VERSION 5.8 ;
BUSBITCHARS "[]" ;
DIVIDERCHAR "/" ;
UNITS
    DATABASE MICRONS 1000 ;
END UNITS

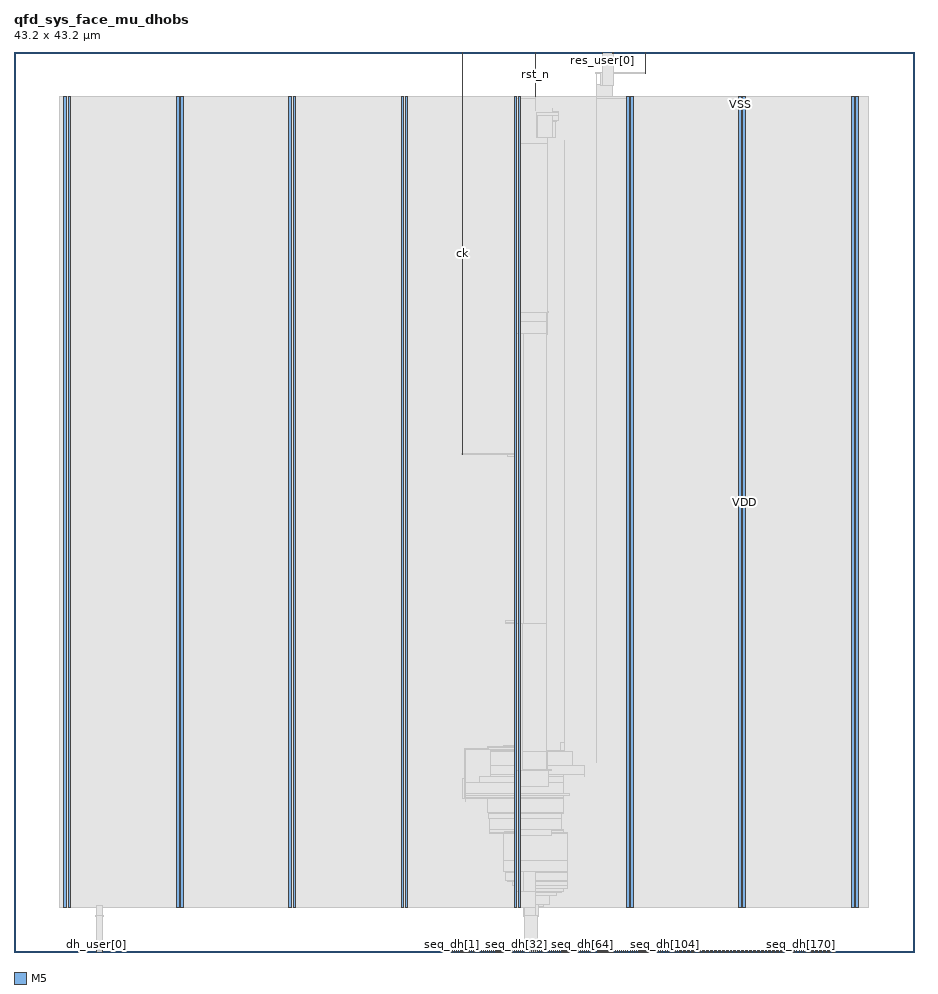
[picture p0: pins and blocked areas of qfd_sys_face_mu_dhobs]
MACRO qfd_sys_face_mu_dhobs
  FOREIGN qfd_sys_face_mu_dhobs 0 0 ;
  CLASS BLOCK ;
  SIZE 43.2 BY 43.2 ;
  PIN ck
    DIRECTION INPUT ;
    USE SIGNAL ;
    PORT
      LAYER M5 ;
        RECT  21.504 43.116 21.528 43.2 ;
    END
    PORT
      LAYER M5 ;
        RECT  21.504 23.893 21.528 43.152 ;
    END
  END ck
  PIN dh_user[0]
    DIRECTION OUTPUT ;
    USE SIGNAL ;
    PORT
      LAYER M5 ;
        RECT  3.936 0 3.96 0.084 ;
    END
  END dh_user[0]
  PIN dh_user[1]
    DIRECTION OUTPUT ;
    USE SIGNAL ;
    PORT
      LAYER M5 ;
        RECT  4.224 0 4.248 0.084 ;
    END
  END dh_user[1]
  PIN mu_fault
    DIRECTION OUTPUT ;
    USE SIGNAL ;
    PORT
      LAYER M5 ;
        RECT  30.288 43.116 30.312 43.2 ;
    END
    PORT
      LAYER M5 ;
        RECT  30.288 42.181 30.312 43.152 ;
    END
  END mu_fault
  PIN res_user[0]
    DIRECTION OUTPUT ;
    USE SIGNAL ;
    PORT
      LAYER M5 ;
        RECT  28.224 43.116 28.248 43.2 ;
    END
  END res_user[0]
  PIN res_user[1]
    DIRECTION OUTPUT ;
    USE SIGNAL ;
    PORT
      LAYER M5 ;
        RECT  28.752 43.116 28.776 43.2 ;
    END
  END res_user[1]
  PIN rst_n
    DIRECTION INPUT ;
    USE SIGNAL ;
    PORT
      LAYER M5 ;
        RECT  25.008 43.116 25.032 43.2 ;
    END
    PORT
      LAYER M5 ;
        RECT  25.008 41.063 25.032 43.152 ;
    END
  END rst_n
  PIN seq_dh[0]
    DIRECTION INPUT ;
    USE SIGNAL ;
    PORT
      LAYER M5 ;
        RECT  20.928 0 20.952 0.084 ;
    END
  END seq_dh[0]
  PIN seq_dh[100]
    DIRECTION INPUT ;
    USE SIGNAL ;
    PORT
      LAYER M5 ;
        RECT  30.816 0 30.84 0.084 ;
    END
  END seq_dh[100]
  PIN seq_dh[101]
    DIRECTION INPUT ;
    USE SIGNAL ;
    PORT
      LAYER M5 ;
        RECT  30.912 0 30.936 0.084 ;
    END
  END seq_dh[101]
  PIN seq_dh[102]
    DIRECTION INPUT ;
    USE SIGNAL ;
    PORT
      LAYER M5 ;
        RECT  31.008 0 31.032 0.084 ;
    END
  END seq_dh[102]
  PIN seq_dh[103]
    DIRECTION INPUT ;
    USE SIGNAL ;
    PORT
      LAYER M5 ;
        RECT  31.104 0 31.128 0.084 ;
    END
  END seq_dh[103]
  PIN seq_dh[104]
    DIRECTION INPUT ;
    USE SIGNAL ;
    PORT
      LAYER M5 ;
        RECT  31.248 0 31.272 0.084 ;
    END
  END seq_dh[104]
  PIN seq_dh[105]
    DIRECTION INPUT ;
    USE SIGNAL ;
    PORT
      LAYER M5 ;
        RECT  31.344 0 31.368 0.084 ;
    END
  END seq_dh[105]
  PIN seq_dh[106]
    DIRECTION INPUT ;
    USE SIGNAL ;
    PORT
      LAYER M5 ;
        RECT  31.44 0 31.464 0.084 ;
    END
  END seq_dh[106]
  PIN seq_dh[107]
    DIRECTION INPUT ;
    USE SIGNAL ;
    PORT
      LAYER M5 ;
        RECT  31.536 0 31.56 0.084 ;
    END
  END seq_dh[107]
  PIN seq_dh[108]
    DIRECTION INPUT ;
    USE SIGNAL ;
    PORT
      LAYER M5 ;
        RECT  31.632 0 31.656 0.084 ;
    END
  END seq_dh[108]
  PIN seq_dh[109]
    DIRECTION INPUT ;
    USE SIGNAL ;
    PORT
      LAYER M5 ;
        RECT  31.728 0 31.752 0.084 ;
    END
  END seq_dh[109]
  PIN seq_dh[10]
    DIRECTION INPUT ;
    USE SIGNAL ;
    PORT
      LAYER M5 ;
        RECT  21.936 0 21.96 0.084 ;
    END
  END seq_dh[10]
  PIN seq_dh[110]
    DIRECTION INPUT ;
    USE SIGNAL ;
    PORT
      LAYER M5 ;
        RECT  31.824 0 31.848 0.084 ;
    END
  END seq_dh[110]
  PIN seq_dh[111]
    DIRECTION INPUT ;
    USE SIGNAL ;
    PORT
      LAYER M5 ;
        RECT  31.92 0 31.944 0.084 ;
    END
  END seq_dh[111]
  PIN seq_dh[112]
    DIRECTION INPUT ;
    USE SIGNAL ;
    PORT
      LAYER M5 ;
        RECT  32.016 0 32.04 0.084 ;
    END
  END seq_dh[112]
  PIN seq_dh[113]
    DIRECTION INPUT ;
    USE SIGNAL ;
    PORT
      LAYER M5 ;
        RECT  32.112 0 32.136 0.084 ;
    END
  END seq_dh[113]
  PIN seq_dh[114]
    DIRECTION INPUT ;
    USE SIGNAL ;
    PORT
      LAYER M5 ;
        RECT  32.208 0 32.232 0.084 ;
    END
  END seq_dh[114]
  PIN seq_dh[115]
    DIRECTION INPUT ;
    USE SIGNAL ;
    PORT
      LAYER M5 ;
        RECT  32.304 0 32.328 0.084 ;
    END
  END seq_dh[115]
  PIN seq_dh[116]
    DIRECTION INPUT ;
    USE SIGNAL ;
    PORT
      LAYER M5 ;
        RECT  32.4 0 32.424 0.084 ;
    END
  END seq_dh[116]
  PIN seq_dh[117]
    DIRECTION INPUT ;
    USE SIGNAL ;
    PORT
      LAYER M5 ;
        RECT  32.496 0 32.52 0.084 ;
    END
  END seq_dh[117]
  PIN seq_dh[118]
    DIRECTION INPUT ;
    USE SIGNAL ;
    PORT
      LAYER M5 ;
        RECT  32.592 0 32.616 0.084 ;
    END
  END seq_dh[118]
  PIN seq_dh[119]
    DIRECTION INPUT ;
    USE SIGNAL ;
    PORT
      LAYER M5 ;
        RECT  32.688 0 32.712 0.084 ;
    END
  END seq_dh[119]
  PIN seq_dh[11]
    DIRECTION INPUT ;
    USE SIGNAL ;
    PORT
      LAYER M5 ;
        RECT  22.032 0 22.056 0.084 ;
    END
  END seq_dh[11]
  PIN seq_dh[120]
    DIRECTION INPUT ;
    USE SIGNAL ;
    PORT
      LAYER M5 ;
        RECT  32.832 0 32.856 0.084 ;
    END
  END seq_dh[120]
  PIN seq_dh[121]
    DIRECTION INPUT ;
    USE SIGNAL ;
    PORT
      LAYER M5 ;
        RECT  32.928 0 32.952 0.084 ;
    END
  END seq_dh[121]
  PIN seq_dh[122]
    DIRECTION INPUT ;
    USE SIGNAL ;
    PORT
      LAYER M5 ;
        RECT  33.024 0 33.048 0.084 ;
    END
  END seq_dh[122]
  PIN seq_dh[123]
    DIRECTION INPUT ;
    USE SIGNAL ;
    PORT
      LAYER M5 ;
        RECT  33.12 0 33.144 0.084 ;
    END
  END seq_dh[123]
  PIN seq_dh[124]
    DIRECTION INPUT ;
    USE SIGNAL ;
    PORT
      LAYER M5 ;
        RECT  33.216 0 33.24 0.084 ;
    END
  END seq_dh[124]
  PIN seq_dh[125]
    DIRECTION INPUT ;
    USE SIGNAL ;
    PORT
      LAYER M5 ;
        RECT  33.312 0 33.336 0.084 ;
    END
  END seq_dh[125]
  PIN seq_dh[126]
    DIRECTION INPUT ;
    USE SIGNAL ;
    PORT
      LAYER M5 ;
        RECT  33.408 0 33.432 0.084 ;
    END
  END seq_dh[126]
  PIN seq_dh[127]
    DIRECTION INPUT ;
    USE SIGNAL ;
    PORT
      LAYER M5 ;
        RECT  33.504 0 33.528 0.084 ;
    END
  END seq_dh[127]
  PIN seq_dh[128]
    DIRECTION INPUT ;
    USE SIGNAL ;
    PORT
      LAYER M5 ;
        RECT  33.6 0 33.624 0.084 ;
    END
  END seq_dh[128]
  PIN seq_dh[129]
    DIRECTION INPUT ;
    USE SIGNAL ;
    PORT
      LAYER M5 ;
        RECT  33.696 0 33.72 0.084 ;
    END
  END seq_dh[129]
  PIN seq_dh[12]
    DIRECTION INPUT ;
    USE SIGNAL ;
    PORT
      LAYER M5 ;
        RECT  22.128 0 22.152 0.084 ;
    END
  END seq_dh[12]
  PIN seq_dh[130]
    DIRECTION INPUT ;
    USE SIGNAL ;
    PORT
      LAYER M5 ;
        RECT  33.792 0 33.816 0.084 ;
    END
  END seq_dh[130]
  PIN seq_dh[131]
    DIRECTION INPUT ;
    USE SIGNAL ;
    PORT
      LAYER M5 ;
        RECT  33.888 0 33.912 0.084 ;
    END
  END seq_dh[131]
  PIN seq_dh[132]
    DIRECTION INPUT ;
    USE SIGNAL ;
    PORT
      LAYER M5 ;
        RECT  33.984 0 34.008 0.084 ;
    END
  END seq_dh[132]
  PIN seq_dh[133]
    DIRECTION INPUT ;
    USE SIGNAL ;
    PORT
      LAYER M5 ;
        RECT  34.08 0 34.104 0.084 ;
    END
  END seq_dh[133]
  PIN seq_dh[134]
    DIRECTION INPUT ;
    USE SIGNAL ;
    PORT
      LAYER M5 ;
        RECT  34.176 0 34.2 0.084 ;
    END
  END seq_dh[134]
  PIN seq_dh[135]
    DIRECTION INPUT ;
    USE SIGNAL ;
    PORT
      LAYER M5 ;
        RECT  34.272 0 34.296 0.084 ;
    END
  END seq_dh[135]
  PIN seq_dh[136]
    DIRECTION INPUT ;
    USE SIGNAL ;
    PORT
      LAYER M5 ;
        RECT  34.416 0 34.44 0.084 ;
    END
  END seq_dh[136]
  PIN seq_dh[137]
    DIRECTION INPUT ;
    USE SIGNAL ;
    PORT
      LAYER M5 ;
        RECT  34.512 0 34.536 0.084 ;
    END
  END seq_dh[137]
  PIN seq_dh[138]
    DIRECTION INPUT ;
    USE SIGNAL ;
    PORT
      LAYER M5 ;
        RECT  34.608 0 34.632 0.084 ;
    END
  END seq_dh[138]
  PIN seq_dh[139]
    DIRECTION INPUT ;
    USE SIGNAL ;
    PORT
      LAYER M5 ;
        RECT  34.704 0 34.728 0.084 ;
    END
  END seq_dh[139]
  PIN seq_dh[13]
    DIRECTION INPUT ;
    USE SIGNAL ;
    PORT
      LAYER M5 ;
        RECT  22.224 0 22.248 0.084 ;
    END
  END seq_dh[13]
  PIN seq_dh[140]
    DIRECTION INPUT ;
    USE SIGNAL ;
    PORT
      LAYER M5 ;
        RECT  34.8 0 34.824 0.084 ;
    END
  END seq_dh[140]
  PIN seq_dh[141]
    DIRECTION INPUT ;
    USE SIGNAL ;
    PORT
      LAYER M5 ;
        RECT  34.896 0 34.92 0.084 ;
    END
  END seq_dh[141]
  PIN seq_dh[142]
    DIRECTION INPUT ;
    USE SIGNAL ;
    PORT
      LAYER M5 ;
        RECT  34.992 0 35.016 0.084 ;
    END
  END seq_dh[142]
  PIN seq_dh[143]
    DIRECTION INPUT ;
    USE SIGNAL ;
    PORT
      LAYER M5 ;
        RECT  35.088 0 35.112 0.084 ;
    END
  END seq_dh[143]
  PIN seq_dh[144]
    DIRECTION INPUT ;
    USE SIGNAL ;
    PORT
      LAYER M5 ;
        RECT  35.184 0 35.208 0.084 ;
    END
  END seq_dh[144]
  PIN seq_dh[145]
    DIRECTION INPUT ;
    USE SIGNAL ;
    PORT
      LAYER M5 ;
        RECT  35.28 0 35.304 0.084 ;
    END
  END seq_dh[145]
  PIN seq_dh[146]
    DIRECTION INPUT ;
    USE SIGNAL ;
    PORT
      LAYER M5 ;
        RECT  35.376 0 35.4 0.084 ;
    END
  END seq_dh[146]
  PIN seq_dh[147]
    DIRECTION INPUT ;
    USE SIGNAL ;
    PORT
      LAYER M5 ;
        RECT  35.472 0 35.496 0.084 ;
    END
  END seq_dh[147]
  PIN seq_dh[148]
    DIRECTION INPUT ;
    USE SIGNAL ;
    PORT
      LAYER M5 ;
        RECT  35.568 0 35.592 0.084 ;
    END
  END seq_dh[148]
  PIN seq_dh[149]
    DIRECTION INPUT ;
    USE SIGNAL ;
    PORT
      LAYER M5 ;
        RECT  35.664 0 35.688 0.084 ;
    END
  END seq_dh[149]
  PIN seq_dh[14]
    DIRECTION INPUT ;
    USE SIGNAL ;
    PORT
      LAYER M5 ;
        RECT  22.32 0 22.344 0.084 ;
    END
  END seq_dh[14]
  PIN seq_dh[150]
    DIRECTION INPUT ;
    USE SIGNAL ;
    PORT
      LAYER M5 ;
        RECT  35.76 0 35.784 0.084 ;
    END
  END seq_dh[150]
  PIN seq_dh[151]
    DIRECTION INPUT ;
    USE SIGNAL ;
    PORT
      LAYER M5 ;
        RECT  35.856 0 35.88 0.084 ;
    END
  END seq_dh[151]
  PIN seq_dh[152]
    DIRECTION INPUT ;
    USE SIGNAL ;
    PORT
      LAYER M5 ;
        RECT  35.952 0 35.976 0.084 ;
    END
  END seq_dh[152]
  PIN seq_dh[153]
    DIRECTION INPUT ;
    USE SIGNAL ;
    PORT
      LAYER M5 ;
        RECT  36.096 0 36.12 0.084 ;
    END
  END seq_dh[153]
  PIN seq_dh[154]
    DIRECTION INPUT ;
    USE SIGNAL ;
    PORT
      LAYER M5 ;
        RECT  36.192 0 36.216 0.084 ;
    END
  END seq_dh[154]
  PIN seq_dh[155]
    DIRECTION INPUT ;
    USE SIGNAL ;
    PORT
      LAYER M5 ;
        RECT  36.288 0 36.312 0.084 ;
    END
  END seq_dh[155]
  PIN seq_dh[156]
    DIRECTION INPUT ;
    USE SIGNAL ;
    PORT
      LAYER M5 ;
        RECT  36.384 0 36.408 0.084 ;
    END
  END seq_dh[156]
  PIN seq_dh[157]
    DIRECTION INPUT ;
    USE SIGNAL ;
    PORT
      LAYER M5 ;
        RECT  36.48 0 36.504 0.084 ;
    END
  END seq_dh[157]
  PIN seq_dh[158]
    DIRECTION INPUT ;
    USE SIGNAL ;
    PORT
      LAYER M5 ;
        RECT  36.576 0 36.6 0.084 ;
    END
  END seq_dh[158]
  PIN seq_dh[159]
    DIRECTION INPUT ;
    USE SIGNAL ;
    PORT
      LAYER M5 ;
        RECT  36.672 0 36.696 0.084 ;
    END
  END seq_dh[159]
  PIN seq_dh[15]
    DIRECTION INPUT ;
    USE SIGNAL ;
    PORT
      LAYER M5 ;
        RECT  22.416 0 22.44 0.084 ;
    END
  END seq_dh[15]
  PIN seq_dh[160]
    DIRECTION INPUT ;
    USE SIGNAL ;
    PORT
      LAYER M5 ;
        RECT  36.768 0 36.792 0.084 ;
    END
  END seq_dh[160]
  PIN seq_dh[161]
    DIRECTION INPUT ;
    USE SIGNAL ;
    PORT
      LAYER M5 ;
        RECT  36.864 0 36.888 0.084 ;
    END
  END seq_dh[161]
  PIN seq_dh[162]
    DIRECTION INPUT ;
    USE SIGNAL ;
    PORT
      LAYER M5 ;
        RECT  36.96 0 36.984 0.084 ;
    END
  END seq_dh[162]
  PIN seq_dh[163]
    DIRECTION INPUT ;
    USE SIGNAL ;
    PORT
      LAYER M5 ;
        RECT  37.056 0 37.08 0.084 ;
    END
  END seq_dh[163]
  PIN seq_dh[164]
    DIRECTION INPUT ;
    USE SIGNAL ;
    PORT
      LAYER M5 ;
        RECT  37.152 0 37.176 0.084 ;
    END
  END seq_dh[164]
  PIN seq_dh[165]
    DIRECTION INPUT ;
    USE SIGNAL ;
    PORT
      LAYER M5 ;
        RECT  37.248 0 37.272 0.084 ;
    END
  END seq_dh[165]
  PIN seq_dh[166]
    DIRECTION INPUT ;
    USE SIGNAL ;
    PORT
      LAYER M5 ;
        RECT  37.344 0 37.368 0.084 ;
    END
  END seq_dh[166]
  PIN seq_dh[167]
    DIRECTION INPUT ;
    USE SIGNAL ;
    PORT
      LAYER M5 ;
        RECT  37.44 0 37.464 0.084 ;
    END
  END seq_dh[167]
  PIN seq_dh[168]
    DIRECTION INPUT ;
    USE SIGNAL ;
    PORT
      LAYER M5 ;
        RECT  37.536 0 37.56 0.084 ;
    END
  END seq_dh[168]
  PIN seq_dh[169]
    DIRECTION INPUT ;
    USE SIGNAL ;
    PORT
      LAYER M5 ;
        RECT  37.68 0 37.704 0.084 ;
    END
  END seq_dh[169]
  PIN seq_dh[16]
    DIRECTION INPUT ;
    USE SIGNAL ;
    PORT
      LAYER M5 ;
        RECT  22.512 0 22.536 0.084 ;
    END
  END seq_dh[16]
  PIN seq_dh[170]
    DIRECTION INPUT ;
    USE SIGNAL ;
    PORT
      LAYER M5 ;
        RECT  37.776 0 37.8 0.084 ;
    END
  END seq_dh[170]
  PIN seq_dh[171]
    DIRECTION INPUT ;
    USE SIGNAL ;
    PORT
      LAYER M5 ;
        RECT  37.872 0 37.896 0.084 ;
    END
  END seq_dh[171]
  PIN seq_dh[172]
    DIRECTION INPUT ;
    USE SIGNAL ;
    PORT
      LAYER M5 ;
        RECT  37.968 0 37.992 0.084 ;
    END
  END seq_dh[172]
  PIN seq_dh[173]
    DIRECTION INPUT ;
    USE SIGNAL ;
    PORT
      LAYER M5 ;
        RECT  38.064 0 38.088 0.084 ;
    END
  END seq_dh[173]
  PIN seq_dh[174]
    DIRECTION INPUT ;
    USE SIGNAL ;
    PORT
      LAYER M5 ;
        RECT  38.16 0 38.184 0.084 ;
    END
  END seq_dh[174]
  PIN seq_dh[175]
    DIRECTION INPUT ;
    USE SIGNAL ;
    PORT
      LAYER M5 ;
        RECT  38.256 0 38.28 0.084 ;
    END
  END seq_dh[175]
  PIN seq_dh[176]
    DIRECTION INPUT ;
    USE SIGNAL ;
    PORT
      LAYER M5 ;
        RECT  38.352 0 38.376 0.084 ;
    END
  END seq_dh[176]
  PIN seq_dh[177]
    DIRECTION INPUT ;
    USE SIGNAL ;
    PORT
      LAYER M5 ;
        RECT  38.448 0 38.472 0.084 ;
    END
  END seq_dh[177]
  PIN seq_dh[178]
    DIRECTION INPUT ;
    USE SIGNAL ;
    PORT
      LAYER M5 ;
        RECT  38.544 0 38.568 0.084 ;
    END
  END seq_dh[178]
  PIN seq_dh[179]
    DIRECTION INPUT ;
    USE SIGNAL ;
    PORT
      LAYER M5 ;
        RECT  38.64 0 38.664 0.084 ;
    END
  END seq_dh[179]
  PIN seq_dh[17]
    DIRECTION INPUT ;
    USE SIGNAL ;
    PORT
      LAYER M5 ;
        RECT  22.608 0 22.632 0.084 ;
    END
  END seq_dh[17]
  PIN seq_dh[180]
    DIRECTION INPUT ;
    USE SIGNAL ;
    PORT
      LAYER M5 ;
        RECT  38.736 0 38.76 0.084 ;
    END
  END seq_dh[180]
  PIN seq_dh[181]
    DIRECTION INPUT ;
    USE SIGNAL ;
    PORT
      LAYER M5 ;
        RECT  38.832 0 38.856 0.084 ;
    END
  END seq_dh[181]
  PIN seq_dh[182]
    DIRECTION INPUT ;
    USE SIGNAL ;
    PORT
      LAYER M5 ;
        RECT  38.928 0 38.952 0.084 ;
    END
  END seq_dh[182]
  PIN seq_dh[183]
    DIRECTION INPUT ;
    USE SIGNAL ;
    PORT
      LAYER M5 ;
        RECT  39.024 0 39.048 0.084 ;
    END
  END seq_dh[183]
  PIN seq_dh[184]
    DIRECTION INPUT ;
    USE SIGNAL ;
    PORT
      LAYER M5 ;
        RECT  39.12 0 39.144 0.084 ;
    END
  END seq_dh[184]
  PIN seq_dh[185]
    DIRECTION INPUT ;
    USE SIGNAL ;
    PORT
      LAYER M5 ;
        RECT  39.264 0 39.288 0.084 ;
    END
  END seq_dh[185]
  PIN seq_dh[186]
    DIRECTION INPUT ;
    USE SIGNAL ;
    PORT
      LAYER M5 ;
        RECT  39.36 0 39.384 0.084 ;
    END
  END seq_dh[186]
  PIN seq_dh[18]
    DIRECTION INPUT ;
    USE SIGNAL ;
    PORT
      LAYER M5 ;
        RECT  22.704 0 22.728 0.084 ;
    END
  END seq_dh[18]
  PIN seq_dh[19]
    DIRECTION INPUT ;
    USE SIGNAL ;
    PORT
      LAYER M5 ;
        RECT  22.8 0 22.824 0.084 ;
    END
  END seq_dh[19]
  PIN seq_dh[1]
    DIRECTION INPUT ;
    USE SIGNAL ;
    PORT
      LAYER M5 ;
        RECT  21.024 0 21.048 0.084 ;
    END
  END seq_dh[1]
  PIN seq_dh[20]
    DIRECTION INPUT ;
    USE SIGNAL ;
    PORT
      LAYER M5 ;
        RECT  22.896 0 22.92 0.084 ;
    END
  END seq_dh[20]
  PIN seq_dh[21]
    DIRECTION INPUT ;
    USE SIGNAL ;
    PORT
      LAYER M5 ;
        RECT  22.992 0 23.016 0.084 ;
    END
  END seq_dh[21]
  PIN seq_dh[22]
    DIRECTION INPUT ;
    USE SIGNAL ;
    PORT
      LAYER M5 ;
        RECT  23.136 0 23.16 0.084 ;
    END
  END seq_dh[22]
  PIN seq_dh[23]
    DIRECTION INPUT ;
    USE SIGNAL ;
    PORT
      LAYER M5 ;
        RECT  23.232 0 23.256 0.084 ;
    END
  END seq_dh[23]
  PIN seq_dh[24]
    DIRECTION INPUT ;
    USE SIGNAL ;
    PORT
      LAYER M5 ;
        RECT  23.328 0 23.352 0.084 ;
    END
  END seq_dh[24]
  PIN seq_dh[25]
    DIRECTION INPUT ;
    USE SIGNAL ;
    PORT
      LAYER M5 ;
        RECT  23.424 0 23.448 0.084 ;
    END
  END seq_dh[25]
  PIN seq_dh[26]
    DIRECTION INPUT ;
    USE SIGNAL ;
    PORT
      LAYER M5 ;
        RECT  23.52 0 23.544 0.084 ;
    END
  END seq_dh[26]
  PIN seq_dh[27]
    DIRECTION INPUT ;
    USE SIGNAL ;
    PORT
      LAYER M5 ;
        RECT  23.616 0 23.64 0.084 ;
    END
  END seq_dh[27]
  PIN seq_dh[28]
    DIRECTION INPUT ;
    USE SIGNAL ;
    PORT
      LAYER M5 ;
        RECT  23.712 0 23.736 0.084 ;
    END
  END seq_dh[28]
  PIN seq_dh[29]
    DIRECTION INPUT ;
    USE SIGNAL ;
    PORT
      LAYER M5 ;
        RECT  23.808 0 23.832 0.084 ;
    END
  END seq_dh[29]
  PIN seq_dh[2]
    DIRECTION INPUT ;
    USE SIGNAL ;
    PORT
      LAYER M5 ;
        RECT  21.12 0 21.144 0.084 ;
    END
  END seq_dh[2]
  PIN seq_dh[30]
    DIRECTION INPUT ;
    USE SIGNAL ;
    PORT
      LAYER M5 ;
        RECT  23.904 0 23.928 0.084 ;
    END
  END seq_dh[30]
  PIN seq_dh[31]
    DIRECTION INPUT ;
    USE SIGNAL ;
    PORT
      LAYER M5 ;
        RECT  24 0 24.024 0.084 ;
    END
  END seq_dh[31]
  PIN seq_dh[32]
    DIRECTION INPUT ;
    USE SIGNAL ;
    PORT
      LAYER M5 ;
        RECT  24.096 0 24.12 0.084 ;
    END
  END seq_dh[32]
  PIN seq_dh[33]
    DIRECTION INPUT ;
    USE SIGNAL ;
    PORT
      LAYER M5 ;
        RECT  24.192 0 24.216 0.084 ;
    END
  END seq_dh[33]
  PIN seq_dh[34]
    DIRECTION INPUT ;
    USE SIGNAL ;
    PORT
      LAYER M5 ;
        RECT  24.288 0 24.312 0.084 ;
    END
  END seq_dh[34]
  PIN seq_dh[35]
    DIRECTION INPUT ;
    USE SIGNAL ;
    PORT
      LAYER M5 ;
        RECT  24.384 0 24.408 0.084 ;
    END
  END seq_dh[35]
  PIN seq_dh[36]
    DIRECTION INPUT ;
    USE SIGNAL ;
    PORT
      LAYER M5 ;
        RECT  24.48 0 24.504 0.084 ;
    END
  END seq_dh[36]
  PIN seq_dh[37]
    DIRECTION INPUT ;
    USE SIGNAL ;
    PORT
      LAYER M5 ;
        RECT  24.576 0 24.6 0.084 ;
    END
  END seq_dh[37]
  PIN seq_dh[38]
    DIRECTION INPUT ;
    USE SIGNAL ;
    PORT
      LAYER M5 ;
        RECT  24.72 0 24.744 0.084 ;
    END
  END seq_dh[38]
  PIN seq_dh[39]
    DIRECTION INPUT ;
    USE SIGNAL ;
    PORT
      LAYER M5 ;
        RECT  24.816 0 24.84 0.084 ;
    END
  END seq_dh[39]
  PIN seq_dh[3]
    DIRECTION INPUT ;
    USE SIGNAL ;
    PORT
      LAYER M5 ;
        RECT  21.216 0 21.24 0.084 ;
    END
  END seq_dh[3]
  PIN seq_dh[40]
    DIRECTION INPUT ;
    USE SIGNAL ;
    PORT
      LAYER M5 ;
        RECT  24.912 0 24.936 0.084 ;
    END
  END seq_dh[40]
  PIN seq_dh[41]
    DIRECTION INPUT ;
    USE SIGNAL ;
    PORT
      LAYER M5 ;
        RECT  25.008 0 25.032 0.084 ;
    END
  END seq_dh[41]
  PIN seq_dh[42]
    DIRECTION INPUT ;
    USE SIGNAL ;
    PORT
      LAYER M5 ;
        RECT  25.104 0 25.128 0.084 ;
    END
  END seq_dh[42]
  PIN seq_dh[43]
    DIRECTION INPUT ;
    USE SIGNAL ;
    PORT
      LAYER M5 ;
        RECT  25.2 0 25.224 0.084 ;
    END
  END seq_dh[43]
  PIN seq_dh[44]
    DIRECTION INPUT ;
    USE SIGNAL ;
    PORT
      LAYER M5 ;
        RECT  25.296 0 25.32 0.084 ;
    END
  END seq_dh[44]
  PIN seq_dh[45]
    DIRECTION INPUT ;
    USE SIGNAL ;
    PORT
      LAYER M5 ;
        RECT  25.392 0 25.416 0.084 ;
    END
  END seq_dh[45]
  PIN seq_dh[46]
    DIRECTION INPUT ;
    USE SIGNAL ;
    PORT
      LAYER M5 ;
        RECT  25.488 0 25.512 0.084 ;
    END
  END seq_dh[46]
  PIN seq_dh[47]
    DIRECTION INPUT ;
    USE SIGNAL ;
    PORT
      LAYER M5 ;
        RECT  25.584 0 25.608 0.084 ;
    END
  END seq_dh[47]
  PIN seq_dh[48]
    DIRECTION INPUT ;
    USE SIGNAL ;
    PORT
      LAYER M5 ;
        RECT  25.68 0 25.704 0.084 ;
    END
  END seq_dh[48]
  PIN seq_dh[49]
    DIRECTION INPUT ;
    USE SIGNAL ;
    PORT
      LAYER M5 ;
        RECT  25.776 0 25.8 0.084 ;
    END
  END seq_dh[49]
  PIN seq_dh[4]
    DIRECTION INPUT ;
    USE SIGNAL ;
    PORT
      LAYER M5 ;
        RECT  21.312 0 21.336 0.084 ;
    END
  END seq_dh[4]
  PIN seq_dh[50]
    DIRECTION INPUT ;
    USE SIGNAL ;
    PORT
      LAYER M5 ;
        RECT  25.872 0 25.896 0.084 ;
    END
  END seq_dh[50]
  PIN seq_dh[51]
    DIRECTION INPUT ;
    USE SIGNAL ;
    PORT
      LAYER M5 ;
        RECT  25.968 0 25.992 0.084 ;
    END
  END seq_dh[51]
  PIN seq_dh[52]
    DIRECTION INPUT ;
    USE SIGNAL ;
    PORT
      LAYER M5 ;
        RECT  26.064 0 26.088 0.084 ;
    END
  END seq_dh[52]
  PIN seq_dh[53]
    DIRECTION INPUT ;
    USE SIGNAL ;
    PORT
      LAYER M5 ;
        RECT  26.16 0 26.184 0.084 ;
    END
  END seq_dh[53]
  PIN seq_dh[54]
    DIRECTION INPUT ;
    USE SIGNAL ;
    PORT
      LAYER M5 ;
        RECT  26.304 0 26.328 0.084 ;
    END
  END seq_dh[54]
  PIN seq_dh[55]
    DIRECTION INPUT ;
    USE SIGNAL ;
    PORT
      LAYER M5 ;
        RECT  26.4 0 26.424 0.084 ;
    END
  END seq_dh[55]
  PIN seq_dh[56]
    DIRECTION INPUT ;
    USE SIGNAL ;
    PORT
      LAYER M5 ;
        RECT  26.496 0 26.52 0.084 ;
    END
  END seq_dh[56]
  PIN seq_dh[57]
    DIRECTION INPUT ;
    USE SIGNAL ;
    PORT
      LAYER M5 ;
        RECT  26.592 0 26.616 0.084 ;
    END
  END seq_dh[57]
  PIN seq_dh[58]
    DIRECTION INPUT ;
    USE SIGNAL ;
    PORT
      LAYER M5 ;
        RECT  26.688 0 26.712 0.084 ;
    END
  END seq_dh[58]
  PIN seq_dh[59]
    DIRECTION INPUT ;
    USE SIGNAL ;
    PORT
      LAYER M5 ;
        RECT  26.784 0 26.808 0.084 ;
    END
  END seq_dh[59]
  PIN seq_dh[5]
    DIRECTION INPUT ;
    USE SIGNAL ;
    PORT
      LAYER M5 ;
        RECT  21.456 0 21.48 0.084 ;
    END
  END seq_dh[5]
  PIN seq_dh[60]
    DIRECTION INPUT ;
    USE SIGNAL ;
    PORT
      LAYER M5 ;
        RECT  26.88 0 26.904 0.084 ;
    END
  END seq_dh[60]
  PIN seq_dh[61]
    DIRECTION INPUT ;
    USE SIGNAL ;
    PORT
      LAYER M5 ;
        RECT  26.976 0 27 0.084 ;
    END
  END seq_dh[61]
  PIN seq_dh[62]
    DIRECTION INPUT ;
    USE SIGNAL ;
    PORT
      LAYER M5 ;
        RECT  27.072 0 27.096 0.084 ;
    END
  END seq_dh[62]
  PIN seq_dh[63]
    DIRECTION INPUT ;
    USE SIGNAL ;
    PORT
      LAYER M5 ;
        RECT  27.168 0 27.192 0.084 ;
    END
  END seq_dh[63]
  PIN seq_dh[64]
    DIRECTION INPUT ;
    USE SIGNAL ;
    PORT
      LAYER M5 ;
        RECT  27.264 0 27.288 0.084 ;
    END
  END seq_dh[64]
  PIN seq_dh[65]
    DIRECTION INPUT ;
    USE SIGNAL ;
    PORT
      LAYER M5 ;
        RECT  27.36 0 27.384 0.084 ;
    END
  END seq_dh[65]
  PIN seq_dh[66]
    DIRECTION INPUT ;
    USE SIGNAL ;
    PORT
      LAYER M5 ;
        RECT  27.456 0 27.48 0.084 ;
    END
  END seq_dh[66]
  PIN seq_dh[67]
    DIRECTION INPUT ;
    USE SIGNAL ;
    PORT
      LAYER M5 ;
        RECT  27.552 0 27.576 0.084 ;
    END
  END seq_dh[67]
  PIN seq_dh[68]
    DIRECTION INPUT ;
    USE SIGNAL ;
    PORT
      LAYER M5 ;
        RECT  27.648 0 27.672 0.084 ;
    END
  END seq_dh[68]
  PIN seq_dh[69]
    DIRECTION INPUT ;
    USE SIGNAL ;
    PORT
      LAYER M5 ;
        RECT  27.744 0 27.768 0.084 ;
    END
  END seq_dh[69]
  PIN seq_dh[6]
    DIRECTION INPUT ;
    USE SIGNAL ;
    PORT
      LAYER M5 ;
        RECT  21.552 0 21.576 0.084 ;
    END
  END seq_dh[6]
  PIN seq_dh[70]
    DIRECTION INPUT ;
    USE SIGNAL ;
    PORT
      LAYER M5 ;
        RECT  27.84 0 27.864 0.084 ;
    END
  END seq_dh[70]
  PIN seq_dh[71]
    DIRECTION INPUT ;
    USE SIGNAL ;
    PORT
      LAYER M5 ;
        RECT  27.984 0 28.008 0.084 ;
    END
  END seq_dh[71]
  PIN seq_dh[72]
    DIRECTION INPUT ;
    USE SIGNAL ;
    PORT
      LAYER M5 ;
        RECT  28.08 0 28.104 0.084 ;
    END
  END seq_dh[72]
  PIN seq_dh[73]
    DIRECTION INPUT ;
    USE SIGNAL ;
    PORT
      LAYER M5 ;
        RECT  28.176 0 28.2 0.084 ;
    END
  END seq_dh[73]
  PIN seq_dh[74]
    DIRECTION INPUT ;
    USE SIGNAL ;
    PORT
      LAYER M5 ;
        RECT  28.272 0 28.296 0.084 ;
    END
  END seq_dh[74]
  PIN seq_dh[75]
    DIRECTION INPUT ;
    USE SIGNAL ;
    PORT
      LAYER M5 ;
        RECT  28.368 0 28.392 0.084 ;
    END
  END seq_dh[75]
  PIN seq_dh[76]
    DIRECTION INPUT ;
    USE SIGNAL ;
    PORT
      LAYER M5 ;
        RECT  28.464 0 28.488 0.084 ;
    END
  END seq_dh[76]
  PIN seq_dh[77]
    DIRECTION INPUT ;
    USE SIGNAL ;
    PORT
      LAYER M5 ;
        RECT  28.56 0 28.584 0.084 ;
    END
  END seq_dh[77]
  PIN seq_dh[78]
    DIRECTION INPUT ;
    USE SIGNAL ;
    PORT
      LAYER M5 ;
        RECT  28.656 0 28.68 0.084 ;
    END
  END seq_dh[78]
  PIN seq_dh[79]
    DIRECTION INPUT ;
    USE SIGNAL ;
    PORT
      LAYER M5 ;
        RECT  28.752 0 28.776 0.084 ;
    END
  END seq_dh[79]
  PIN seq_dh[7]
    DIRECTION INPUT ;
    USE SIGNAL ;
    PORT
      LAYER M5 ;
        RECT  21.648 0 21.672 0.084 ;
    END
  END seq_dh[7]
  PIN seq_dh[80]
    DIRECTION INPUT ;
    USE SIGNAL ;
    PORT
      LAYER M5 ;
        RECT  28.848 0 28.872 0.084 ;
    END
  END seq_dh[80]
  PIN seq_dh[81]
    DIRECTION INPUT ;
    USE SIGNAL ;
    PORT
      LAYER M5 ;
        RECT  28.944 0 28.968 0.084 ;
    END
  END seq_dh[81]
  PIN seq_dh[82]
    DIRECTION INPUT ;
    USE SIGNAL ;
    PORT
      LAYER M5 ;
        RECT  29.04 0 29.064 0.084 ;
    END
  END seq_dh[82]
  PIN seq_dh[83]
    DIRECTION INPUT ;
    USE SIGNAL ;
    PORT
      LAYER M5 ;
        RECT  29.136 0 29.16 0.084 ;
    END
  END seq_dh[83]
  PIN seq_dh[84]
    DIRECTION INPUT ;
    USE SIGNAL ;
    PORT
      LAYER M5 ;
        RECT  29.232 0 29.256 0.084 ;
    END
  END seq_dh[84]
  PIN seq_dh[85]
    DIRECTION INPUT ;
    USE SIGNAL ;
    PORT
      LAYER M5 ;
        RECT  29.328 0 29.352 0.084 ;
    END
  END seq_dh[85]
  PIN seq_dh[86]
    DIRECTION INPUT ;
    USE SIGNAL ;
    PORT
      LAYER M5 ;
        RECT  29.424 0 29.448 0.084 ;
    END
  END seq_dh[86]
  PIN seq_dh[87]
    DIRECTION INPUT ;
    USE SIGNAL ;
    PORT
      LAYER M5 ;
        RECT  29.568 0 29.592 0.084 ;
    END
  END seq_dh[87]
  PIN seq_dh[88]
    DIRECTION INPUT ;
    USE SIGNAL ;
    PORT
      LAYER M5 ;
        RECT  29.664 0 29.688 0.084 ;
    END
  END seq_dh[88]
  PIN seq_dh[89]
    DIRECTION INPUT ;
    USE SIGNAL ;
    PORT
      LAYER M5 ;
        RECT  29.76 0 29.784 0.084 ;
    END
  END seq_dh[89]
  PIN seq_dh[8]
    DIRECTION INPUT ;
    USE SIGNAL ;
    PORT
      LAYER M5 ;
        RECT  21.744 0 21.768 0.084 ;
    END
  END seq_dh[8]
  PIN seq_dh[90]
    DIRECTION INPUT ;
    USE SIGNAL ;
    PORT
      LAYER M5 ;
        RECT  29.856 0 29.88 0.084 ;
    END
  END seq_dh[90]
  PIN seq_dh[91]
    DIRECTION INPUT ;
    USE SIGNAL ;
    PORT
      LAYER M5 ;
        RECT  29.952 0 29.976 0.084 ;
    END
  END seq_dh[91]
  PIN seq_dh[92]
    DIRECTION INPUT ;
    USE SIGNAL ;
    PORT
      LAYER M5 ;
        RECT  30.048 0 30.072 0.084 ;
    END
  END seq_dh[92]
  PIN seq_dh[93]
    DIRECTION INPUT ;
    USE SIGNAL ;
    PORT
      LAYER M5 ;
        RECT  30.144 0 30.168 0.084 ;
    END
  END seq_dh[93]
  PIN seq_dh[94]
    DIRECTION INPUT ;
    USE SIGNAL ;
    PORT
      LAYER M5 ;
        RECT  30.24 0 30.264 0.084 ;
    END
  END seq_dh[94]
  PIN seq_dh[95]
    DIRECTION INPUT ;
    USE SIGNAL ;
    PORT
      LAYER M5 ;
        RECT  30.336 0 30.36 0.084 ;
    END
  END seq_dh[95]
  PIN seq_dh[96]
    DIRECTION INPUT ;
    USE SIGNAL ;
    PORT
      LAYER M5 ;
        RECT  30.432 0 30.456 0.084 ;
    END
  END seq_dh[96]
  PIN seq_dh[97]
    DIRECTION INPUT ;
    USE SIGNAL ;
    PORT
      LAYER M5 ;
        RECT  30.528 0 30.552 0.084 ;
    END
  END seq_dh[97]
  PIN seq_dh[98]
    DIRECTION INPUT ;
    USE SIGNAL ;
    PORT
      LAYER M5 ;
        RECT  30.624 0 30.648 0.084 ;
    END
  END seq_dh[98]
  PIN seq_dh[99]
    DIRECTION INPUT ;
    USE SIGNAL ;
    PORT
      LAYER M5 ;
        RECT  30.72 0 30.744 0.084 ;
    END
  END seq_dh[99]
  PIN seq_dh[9]
    DIRECTION INPUT ;
    USE SIGNAL ;
    PORT
      LAYER M5 ;
        RECT  21.84 0 21.864 0.084 ;
    END
  END seq_dh[9]
  PIN VDD
    DIRECTION INOUT ;
    USE POWER ;
    PORT
      LAYER M5 ;
        RECT  40.392 2.151 40.512 41.049 ;
        RECT  34.992 2.151 35.112 41.049 ;
        RECT  29.592 2.151 29.712 41.049 ;
        RECT  24.192 2.151 24.312 41.049 ;
        RECT  18.792 2.151 18.912 41.049 ;
        RECT  13.392 2.151 13.512 41.049 ;
        RECT  7.992 2.151 8.112 41.049 ;
        RECT  2.592 2.151 2.712 41.049 ;
    END
  END VDD
  PIN VSS
    DIRECTION INOUT ;
    USE GROUND ;
    PORT
      LAYER M5 ;
        RECT  40.2 2.137 40.32 41.063 ;
        RECT  34.8 2.137 34.92 41.063 ;
        RECT  29.4 2.137 29.52 41.063 ;
        RECT  24 2.137 24.12 41.063 ;
        RECT  18.6 2.137 18.72 41.063 ;
        RECT  13.2 2.137 13.32 41.063 ;
        RECT  7.8 2.137 7.92 41.063 ;
        RECT  2.4 2.137 2.52 41.063 ;
    END
  END VSS
  # OT_OBS_CLOSED layer=M5 d_um=1.536 added=8
  OBS
    LAYER RVTN ;
     RECT  2.16 2.16 41.04 2.295 ;
     RECT  2.16 2.565 41.04 2.835 ;
     RECT  2.16 3.105 41.04 3.375 ;
     RECT  2.16 3.645 41.04 3.915 ;
     RECT  2.16 4.185 41.04 4.455 ;
     RECT  2.16 4.725 41.04 4.995 ;
     RECT  2.16 5.265 41.04 5.535 ;
     RECT  2.16 5.805 41.04 6.075 ;
     RECT  2.16 6.345 41.04 6.615 ;
     RECT  2.16 6.885 41.04 7.155 ;
     RECT  2.16 7.425 41.04 7.695 ;
     RECT  2.16 7.965 41.04 8.235 ;
     RECT  2.16 8.505 41.04 8.775 ;
     RECT  2.16 9.045 41.04 9.315 ;
     RECT  2.16 9.585 41.04 9.855 ;
     RECT  2.16 10.125 41.04 10.395 ;
     RECT  2.16 10.665 41.04 10.935 ;
     RECT  2.16 11.205 41.04 11.475 ;
     RECT  2.16 11.745 41.04 12.015 ;
     RECT  2.16 12.285 41.04 12.555 ;
     RECT  2.16 12.825 41.04 13.095 ;
     RECT  2.16 13.365 41.04 13.635 ;
     RECT  2.16 13.905 41.04 14.175 ;
     RECT  2.16 14.445 41.04 14.715 ;
     RECT  2.16 14.985 41.04 15.255 ;
     RECT  2.16 15.525 41.04 15.795 ;
     RECT  2.16 16.065 41.04 16.335 ;
     RECT  2.16 16.605 41.04 16.875 ;
     RECT  2.16 17.145 41.04 17.415 ;
     RECT  2.16 17.685 41.04 17.955 ;
     RECT  2.16 18.225 41.04 18.495 ;
     RECT  2.16 18.765 41.04 19.035 ;
     RECT  2.16 19.305 41.04 19.575 ;
     RECT  2.16 19.845 41.04 20.115 ;
     RECT  2.16 20.385 41.04 20.655 ;
     RECT  2.16 20.925 41.04 21.195 ;
     RECT  2.16 21.465 41.04 21.735 ;
     RECT  2.16 22.005 41.04 22.275 ;
     RECT  2.16 22.545 41.04 22.815 ;
     RECT  2.16 23.085 41.04 23.355 ;
     RECT  2.16 23.625 41.04 23.895 ;
     RECT  2.16 24.165 41.04 24.435 ;
     RECT  2.16 24.705 41.04 24.975 ;
     RECT  2.16 25.245 41.04 25.515 ;
     RECT  2.16 25.785 41.04 26.055 ;
     RECT  2.16 26.325 41.04 26.595 ;
     RECT  2.16 26.865 41.04 27.135 ;
     RECT  2.16 27.405 41.04 27.675 ;
     RECT  2.16 27.945 41.04 28.215 ;
     RECT  2.16 28.485 41.04 28.755 ;
     RECT  2.16 29.025 41.04 29.295 ;
     RECT  2.16 29.565 41.04 29.835 ;
     RECT  2.16 30.105 41.04 30.375 ;
     RECT  2.16 30.645 41.04 30.915 ;
     RECT  2.16 31.185 41.04 31.455 ;
     RECT  2.16 31.725 41.04 31.995 ;
     RECT  2.16 32.265 41.04 32.535 ;
     RECT  2.16 32.805 41.04 33.075 ;
     RECT  2.16 33.345 41.04 33.615 ;
     RECT  2.16 33.885 41.04 34.155 ;
     RECT  2.16 34.425 41.04 34.695 ;
     RECT  2.16 34.965 41.04 35.235 ;
     RECT  2.16 35.505 41.04 35.775 ;
     RECT  2.16 36.045 41.04 36.315 ;
     RECT  2.16 36.585 41.04 36.855 ;
     RECT  2.16 37.125 41.04 37.395 ;
     RECT  2.16 37.665 41.04 37.935 ;
     RECT  2.16 38.205 41.04 38.475 ;
     RECT  2.16 38.745 41.04 39.015 ;
     RECT  2.16 39.285 41.04 39.555 ;
     RECT  2.16 39.825 41.04 40.095 ;
     RECT  2.16 40.365 41.04 40.635 ;
     RECT  2.16 40.905 41.04 41.04 ;
    LAYER RVTP ;
     RECT  2.16 2.295 41.04 2.565 ;
     RECT  2.16 2.835 41.04 3.105 ;
     RECT  2.16 3.375 41.04 3.645 ;
     RECT  2.16 3.915 41.04 4.185 ;
     RECT  2.16 4.455 41.04 4.725 ;
     RECT  2.16 4.995 41.04 5.265 ;
     RECT  2.16 5.535 41.04 5.805 ;
     RECT  2.16 6.075 41.04 6.345 ;
     RECT  2.16 6.615 41.04 6.885 ;
     RECT  2.16 7.155 41.04 7.425 ;
     RECT  2.16 7.695 41.04 7.965 ;
     RECT  2.16 8.235 41.04 8.505 ;
     RECT  2.16 8.775 41.04 9.045 ;
     RECT  2.16 9.315 41.04 9.585 ;
     RECT  2.16 9.855 41.04 10.125 ;
     RECT  2.16 10.395 41.04 10.665 ;
     RECT  2.16 10.935 41.04 11.205 ;
     RECT  2.16 11.475 41.04 11.745 ;
     RECT  2.16 12.015 41.04 12.285 ;
     RECT  2.16 12.555 41.04 12.825 ;
     RECT  2.16 13.095 41.04 13.365 ;
     RECT  2.16 13.635 41.04 13.905 ;
     RECT  2.16 14.175 41.04 14.445 ;
     RECT  2.16 14.715 41.04 14.985 ;
     RECT  2.16 15.255 41.04 15.525 ;
     RECT  2.16 15.795 41.04 16.065 ;
     RECT  2.16 16.335 41.04 16.605 ;
     RECT  2.16 16.875 41.04 17.145 ;
     RECT  2.16 17.415 41.04 17.685 ;
     RECT  2.16 17.955 41.04 18.225 ;
     RECT  2.16 18.495 41.04 18.765 ;
     RECT  2.16 19.035 41.04 19.305 ;
     RECT  2.16 19.575 41.04 19.845 ;
     RECT  2.16 20.115 41.04 20.385 ;
     RECT  2.16 20.655 41.04 20.925 ;
     RECT  2.16 21.195 41.04 21.465 ;
     RECT  2.16 21.735 41.04 22.005 ;
     RECT  2.16 22.275 41.04 22.545 ;
     RECT  2.16 22.815 41.04 23.085 ;
     RECT  2.16 23.355 41.04 23.625 ;
     RECT  2.16 23.895 41.04 24.165 ;
     RECT  2.16 24.435 41.04 24.705 ;
     RECT  2.16 24.975 41.04 25.245 ;
     RECT  2.16 25.515 41.04 25.785 ;
     RECT  2.16 26.055 41.04 26.325 ;
     RECT  2.16 26.595 41.04 26.865 ;
     RECT  2.16 27.135 41.04 27.405 ;
     RECT  2.16 27.675 41.04 27.945 ;
     RECT  2.16 28.215 41.04 28.485 ;
     RECT  2.16 28.755 41.04 29.025 ;
     RECT  2.16 29.295 41.04 29.565 ;
     RECT  2.16 29.835 41.04 30.105 ;
     RECT  2.16 30.375 41.04 30.645 ;
     RECT  2.16 30.915 41.04 31.185 ;
     RECT  2.16 31.455 41.04 31.725 ;
     RECT  2.16 31.995 41.04 32.265 ;
     RECT  2.16 32.535 41.04 32.805 ;
     RECT  2.16 33.075 41.04 33.345 ;
     RECT  2.16 33.615 41.04 33.885 ;
     RECT  2.16 34.155 41.04 34.425 ;
     RECT  2.16 34.695 41.04 34.965 ;
     RECT  2.16 35.235 41.04 35.505 ;
     RECT  2.16 35.775 41.04 36.045 ;
     RECT  2.16 36.315 41.04 36.585 ;
     RECT  2.16 36.855 41.04 37.125 ;
     RECT  2.16 37.395 41.04 37.665 ;
     RECT  2.16 37.935 41.04 38.205 ;
     RECT  2.16 38.475 41.04 38.745 ;
     RECT  2.16 39.015 41.04 39.285 ;
     RECT  2.16 39.555 41.04 39.825 ;
     RECT  2.16 40.095 41.04 40.365 ;
     RECT  2.16 40.635 41.04 40.905 ;
    LAYER M1 ;
     RECT  2.16 2.151 41.04 41.049 ;
    LAYER M2 ;
     RECT  2.16 2.151 41.04 41.049 ;
    LAYER M3 ;
     RECT  24.444 1.723 25.11 2.143 ;
     RECT  24.015 2.143 25.11 2.191 ;
     RECT  3.96 1.723 4.23 2.219 ;
     RECT  24.015 2.191 25.398 2.263 ;
     RECT  2.415 2.143 2.505 2.413 ;
     RECT  7.815 2.143 7.905 2.413 ;
     RECT  13.215 2.143 13.305 2.413 ;
     RECT  18.615 2.143 18.705 2.413 ;
     RECT  29.415 2.143 29.505 2.413 ;
     RECT  34.815 2.143 34.905 2.413 ;
     RECT  40.215 2.143 40.305 2.413 ;
     RECT  24.015 2.263 25.686 2.731 ;
     RECT  24.015 2.731 26.046 2.839 ;
     RECT  24.015 2.839 26.298 2.911 ;
     RECT  24.015 2.911 26.37 3.037 ;
     RECT  24.015 3.037 26.55 3.181 ;
     RECT  23.94 3.181 26.55 3.379 ;
     RECT  23.688 3.379 26.55 3.415 ;
     RECT  23.616 3.415 26.55 3.811 ;
     RECT  23.616 3.811 26.586 3.883 ;
     RECT  23.508 3.883 26.586 4.379 ;
     RECT  23.508 4.379 26.55 5.701 ;
     RECT  22.824 5.701 26.55 5.729 ;
     RECT  22.824 5.729 26.37 5.885 ;
     RECT  22.824 5.885 26.298 6.385 ;
     RECT  22.788 6.385 26.298 6.655 ;
     RECT  22.788 6.655 26.37 6.691 ;
     RECT  21.672 7.231 21.69 7.357 ;
     RECT  22.752 6.691 26.37 7.357 ;
     RECT  21.528 7.357 26.37 7.421 ;
     RECT  21.672 7.421 26.37 7.501 ;
     RECT  21.672 7.501 26.658 7.619 ;
     RECT  21.672 7.619 26.37 8.159 ;
     RECT  21.528 8.275 21.546 8.333 ;
     RECT  22.356 8.159 26.37 8.429 ;
     RECT  22.86 8.429 26.37 8.509 ;
     RECT  27.36 8.401 27.378 8.509 ;
     RECT  22.86 8.509 27.378 8.969 ;
     RECT  22.86 8.969 26.802 9.617 ;
     RECT  25.524 9.617 26.442 9.677 ;
     RECT  22.86 9.617 24.678 9.689 ;
     RECT  22.86 9.689 24.297 9.739 ;
     RECT  22.752 9.739 24.297 9.874 ;
     RECT  23.364 9.874 24.297 9.887 ;
     RECT  23.508 9.887 24.297 9.923 ;
     RECT  26.244 9.677 26.442 10.049 ;
     RECT  24.015 9.923 24.297 15.787 ;
     RECT  23.58 15.787 24.297 15.899 ;
     RECT  24.015 15.899 24.297 23.791 ;
     RECT  23.688 23.791 24.297 23.933 ;
     RECT  25.56 29.659 25.578 30.749 ;
     RECT  26.424 10.049 26.442 38.939 ;
     RECT  25.596 38.779 25.614 39.091 ;
     RECT  25.092 39.091 25.974 39.119 ;
     RECT  25.848 39.119 25.974 39.865 ;
     RECT  25.848 39.865 26.046 39.901 ;
     RECT  25.092 39.119 25.11 40.171 ;
     RECT  25.848 39.901 26.154 40.171 ;
     RECT  25.092 40.171 26.154 40.289 ;
     RECT  25.848 40.289 26.154 40.325 ;
     RECT  25.848 40.325 25.866 40.469 ;
     RECT  2.415 2.413 2.697 40.787 ;
     RECT  7.815 2.413 8.097 40.787 ;
     RECT  13.215 2.413 13.497 40.787 ;
     RECT  18.615 2.413 18.897 40.787 ;
     RECT  24.015 23.933 24.297 40.787 ;
     RECT  29.415 2.413 29.697 40.787 ;
     RECT  34.815 2.413 35.097 40.787 ;
     RECT  40.215 2.413 40.497 40.787 ;
     RECT  27.936 9.085 27.954 40.981 ;
     RECT  29.415 40.787 29.505 40.981 ;
     RECT  25.02 40.405 25.038 41.021 ;
     RECT  2.415 40.787 2.505 41.057 ;
     RECT  7.815 40.787 7.905 41.057 ;
     RECT  13.215 40.787 13.305 41.057 ;
     RECT  18.615 40.787 18.705 41.057 ;
     RECT  24.015 40.787 24.105 41.057 ;
     RECT  27.936 40.981 29.505 41.057 ;
     RECT  34.815 40.787 34.905 41.057 ;
     RECT  40.215 40.787 40.305 41.057 ;
     RECT  27.936 41.057 28.746 41.645 ;
     RECT  27.936 41.645 27.954 42.221 ;
    LAYER M4 ;
     RECT  2.408 2.148 2.512 41.052 ;
     RECT  2.512 2.418 2.704 40.782 ;
     RECT  3.905 1.728 4.285 1.752 ;
     RECT  7.808 2.148 7.912 41.052 ;
     RECT  7.912 2.418 8.104 40.782 ;
     RECT  13.208 2.148 13.312 41.052 ;
     RECT  13.312 2.418 13.504 40.782 ;
     RECT  18.608 2.148 18.712 41.052 ;
     RECT  18.712 2.418 18.904 40.782 ;
     RECT  21.517 7.392 21.683 8.328 ;
     RECT  21.637 9.744 22.741 9.768 ;
     RECT  22.741 9.744 22.781 9.864 ;
     RECT  23.533 5.76 24.008 5.784 ;
     RECT  22.781 9.84 24.008 9.864 ;
     RECT  23.569 15.792 24.008 15.816 ;
     RECT  21.493 23.904 24.008 23.928 ;
     RECT  24.008 2.148 24.112 41.052 ;
     RECT  24.112 2.148 24.304 41.016 ;
     RECT  24.304 8.736 24.419 9.864 ;
     RECT  24.304 15.456 24.419 15.816 ;
     RECT  24.304 2.148 24.433 3.864 ;
     RECT  24.419 15.792 24.467 15.816 ;
     RECT  24.304 23.904 24.467 23.928 ;
     RECT  24.433 1.728 25.043 3.864 ;
     RECT  24.304 40.992 25.049 41.016 ;
     RECT  25.043 1.728 25.165 2.28 ;
     RECT  25.165 2.256 25.193 2.28 ;
     RECT  24.419 8.736 25.369 8.76 ;
     RECT  25.369 7.968 25.513 8.76 ;
     RECT  24.304 29.664 25.525 29.688 ;
     RECT  25.525 29.664 25.549 30.264 ;
     RECT  25.549 29.664 25.589 30.744 ;
     RECT  25.513 7.968 25.597 9.672 ;
     RECT  25.589 30.24 25.612 30.744 ;
     RECT  25.541 38.784 25.625 38.808 ;
     RECT  25.612 30.72 25.633 30.744 ;
     RECT  25.597 7.968 25.667 8.76 ;
     RECT  25.043 3.84 25.769 3.864 ;
     RECT  24.304 5.616 25.805 5.88 ;
     RECT  25.667 8.736 25.805 8.76 ;
     RECT  25.805 5.856 26.381 5.88 ;
     RECT  27.925 42.192 28.172 42.216 ;
     RECT  28.172 41.616 28.787 42.216 ;
     RECT  29.408 2.148 29.512 41.052 ;
     RECT  29.512 2.418 29.704 40.782 ;
     RECT  28.787 42.192 30.323 42.216 ;
     RECT  34.808 2.148 34.912 41.052 ;
     RECT  34.912 2.418 35.104 40.782 ;
     RECT  40.208 2.148 40.312 41.052 ;
     RECT  40.312 2.418 40.504 40.782 ;
    LAYER M5 ;
     RECT  3.96 0.016 4.224 0.084 ;
     RECT  3.936 0.084 4.248 1.763 ;
     RECT  24.504 0.016 24.576 0.084 ;
     RECT  24.6 0.016 24.72 0.084 ;
     RECT  24.744 0.016 24.816 0.084 ;
     RECT  24.84 0.016 24.912 0.084 ;
     RECT  24.936 0.016 25.008 0.084 ;
     RECT  25.032 0.016 25.104 0.084 ;
     RECT  24.48 0.084 25.128 1.763 ;
     RECT  24.48 1.763 25.032 2.137 ;
     RECT  2.4 2.137 2.52 2.151 ;
     RECT  7.8 2.137 7.92 2.151 ;
     RECT  13.2 2.137 13.32 2.151 ;
     RECT  18.6 2.137 18.72 2.151 ;
     RECT  29.4 2.137 29.52 2.151 ;
     RECT  34.8 2.137 34.92 2.151 ;
     RECT  40.2 2.137 40.32 2.151 ;
     RECT  24 2.137 25.032 2.915 ;
     RECT  24 2.915 24.312 8.725 ;
     RECT  25.632 7.957 25.656 8.771 ;
     RECT  21.648 7.381 21.672 9.779 ;
     RECT  24 8.725 24.408 15.781 ;
     RECT  24 15.781 24.456 29.699 ;
     RECT  25.536 9.637 25.56 30.275 ;
     RECT  25.584 30.709 25.608 38.819 ;
     RECT  24 29.699 24.312 40.981 ;
     RECT  2.4 2.151 2.712 41.049 ;
     RECT  7.8 2.151 8.112 41.049 ;
     RECT  13.2 2.151 13.512 41.049 ;
     RECT  18.6 2.151 18.912 41.049 ;
     RECT  29.4 2.151 29.712 41.049 ;
     RECT  34.8 2.151 35.112 41.049 ;
     RECT  40.2 2.151 40.512 41.049 ;
     RECT  2.4 41.049 2.52 41.063 ;
     RECT  7.8 41.049 7.92 41.063 ;
     RECT  13.2 41.049 13.32 41.063 ;
     RECT  18.6 41.049 18.72 41.063 ;
     RECT  24 40.981 25.032 41.063 ;
     RECT  29.4 41.049 29.52 41.063 ;
     RECT  34.8 41.049 34.92 41.063 ;
     RECT  40.2 41.049 40.32 41.063 ;
     RECT  28.224 41.605 28.776 43.116 ;
     RECT  28.248 43.116 28.752 43.152 ;
     RECT  24.312 7.957 25.632 8.725 ;
     RECT  24.408 8.725 25.632 8.771 ;
     RECT  24.408 8.771 25.56 9.637 ;
     RECT  24.408 9.637 25.536 15.781 ;
     RECT  24.456 15.781 25.536 29.699 ;
     RECT  24.312 29.699 25.536 30.275 ;
     RECT  24.312 30.275 25.56 30.709 ;
     RECT  24.312 30.709 25.584 38.819 ;
  END
END qfd_sys_face_mu_dhobs
END LIBRARY
